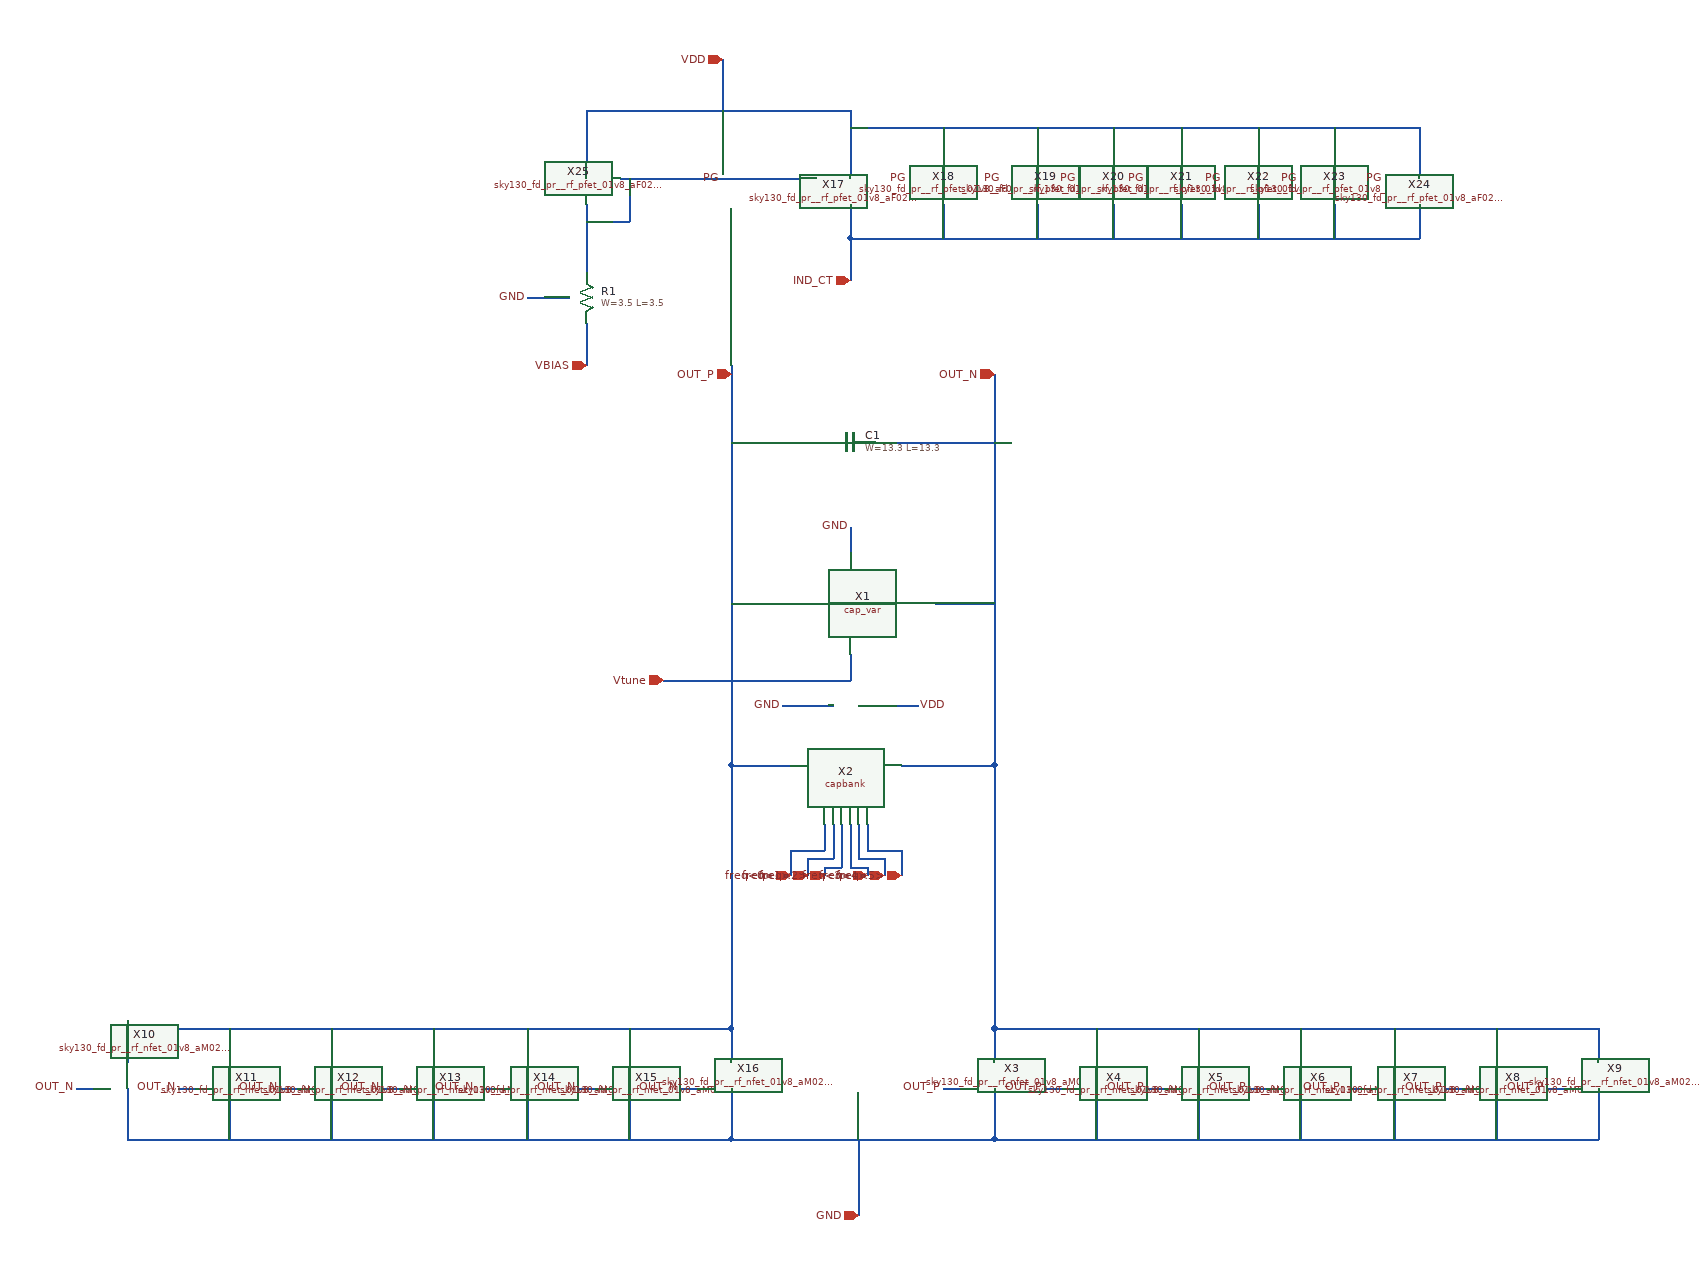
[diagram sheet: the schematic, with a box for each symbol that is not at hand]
v {xschem version=3.0.0 file_version=1.2 }
G {}
K {}
V {}
S {}
E {}
N 290 -420 360 -420 {
lab=OUT_P}
N 290 -820 290 -420 {
lab=OUT_P}
N 290 -800 400 -800 {
lab=OUT_P}
N 290 -610 330 -610 {
lab=OUT_P}
N 490 -420 600 -420 {
lab=OUT_N}
N 600 -820 600 -420 {
lab=OUT_N}
N 460 -800 600 -800 {
lab=OUT_N}
N 530 -610 600 -610 {
lab=OUT_N}
N 290 -890 290 -820 {
lab=OUT_P}
N 600 -880 600 -820 {
lab=OUT_N}
N 430 -550 430 -520 {
lab=Vtune}
N 210 -520 430 -520 {
lab=Vtune}
N 430 -700 430 -670 {
lab=GND}
N 160 -1110 390 -1110 {
lab=PG}
N 430 -1080 430 -1040 {
lab=IND_CT}
N 120 -1190 120 -1140 {
lab=VDD}
N 120 -1190 430 -1190 {
lab=VDD}
N 430 -1190 430 -1140 {
lab=VDD}
N 120 -1140 120 -1110 {
lab=VDD}
N 120 -1080 120 -1000 {
lab=PG}
N 120 -1060 170 -1060 {
lab=PG}
N 170 -1110 170 -1060 {
lab=PG}
N 120 -940 120 -890 {
lab=VBIAS}
N 50 -970 100 -970 {
lab=GND}
N 430 -1140 430 -1110 {
lab=VDD}
N 540 -1080 540 -1040 {
lab=IND_CT}
N 650 -1080 650 -1040 {
lab=IND_CT}
N 740 -1080 740 -1040 {
lab=IND_CT}
N 820 -1080 820 -1040 {
lab=IND_CT}
N 910 -1080 910 -1040 {
lab=IND_CT}
N 1000 -1080 1000 -1040 {
lab=IND_CT}
N 1100 -1080 1100 -1040 {
lab=IND_CT}
N 1100 -1170 1100 -1110 {
lab=VDD}
N 1000 -1170 1000 -1110 {
lab=VDD}
N 910 -1170 910 -1110 {
lab=VDD}
N 820 -1170 820 -1110 {
lab=VDD}
N 740 -1170 740 -1110 {
lab=VDD}
N 650 -1170 650 -1110 {
lab=VDD}
N 540 -1170 540 -1110 {
lab=VDD}
N 430 -1170 1100 -1170 {
lab=VDD}
N 430 -1040 1100 -1040 {
lab=IND_CT}
N 430 -1040 430 -990 {
lab=IND_CT}
N 400 -350 400 -320 {
lab=freq<0>}
N 410 -350 410 -320 {
lab=freq<1>}
N 420 -350 420 -320 {
lab=freq<2>}
N 430 -350 430 -320 {
lab=freq<3>}
N 440 -350 440 -320 {
lab=freq<4>}
N 450 -350 450 -320 {
lab=freq<5>}
N 370 -320 400 -320 {
lab=freq<0>}
N 410 -320 410 -310 {
lab=freq<1>}
N 390 -310 410 -310 {
lab=freq<1>}
N 420 -320 420 -300 {
lab=freq<2>}
N 430 -320 430 -310 {
lab=freq<3>}
N 450 -320 490 -320 {
lab=freq<5>}
N 490 -320 490 -300 {
lab=freq<5>}
N 440 -320 440 -310 {
lab=freq<4>}
N 440 -310 470 -310 {
lab=freq<4>}
N 470 -310 470 -300 {
lab=freq<4>}
N 430 -310 430 -300 {
lab=freq<3>}
N 430 -300 450 -300 {
lab=freq<3>}
N 450 -300 450 -290 {
lab=freq<3>}
N 470 -300 470 -290 {
lab=freq<4>}
N 490 -300 490 -290 {
lab=freq<5>}
N 400 -300 420 -300 {
lab=freq<2>}
N 400 -300 400 -290 {
lab=freq<2>}
N 380 -310 390 -310 {
lab=freq<1>}
N 380 -310 380 -290 {
lab=freq<1>}
N 360 -320 370 -320 {
lab=freq<0>}
N 360 -320 360 -290 {
lab=freq<0>}
N 350 -490 410 -490 {
lab=GND}
N 440 -490 510 -490 {
lab=VDD}
N 280 -1250 280 -1190 {
lab=VDD}
N 600 -40 600 -10 {
lab=GND}
N 600 -10 600 20 {
lab=GND}
N 600 -110 600 -70 {
lab=OUT_N}
N 540 -40 560 -40 {
lab=OUT_P}
N 720 -40 720 -10 {
lab=GND}
N 720 -10 720 20 {
lab=GND}
N 720 -110 720 -70 {
lab=OUT_N}
N 660 -40 680 -40 {
lab=OUT_P}
N 840 -40 840 -10 {
lab=GND}
N 840 -10 840 20 {
lab=GND}
N 840 -110 840 -70 {
lab=OUT_N}
N 780 -40 800 -40 {
lab=OUT_P}
N 960 -40 960 -10 {
lab=GND}
N 960 -10 960 20 {
lab=GND}
N 960 -110 960 -70 {
lab=OUT_N}
N 900 -40 920 -40 {
lab=OUT_P}
N 1070 -40 1070 -10 {
lab=GND}
N 1070 -10 1070 20 {
lab=GND}
N 1070 -110 1070 -70 {
lab=OUT_N}
N 1010 -40 1030 -40 {
lab=OUT_P}
N 1190 -40 1190 -10 {
lab=GND}
N 1190 -10 1190 20 {
lab=GND}
N 1190 -110 1190 -70 {
lab=OUT_N}
N 1130 -40 1150 -40 {
lab=OUT_P}
N 1310 -40 1310 -10 {
lab=GND}
N 1310 -10 1310 20 {
lab=GND}
N 1310 -110 1310 -70 {
lab=OUT_N}
N 1250 -40 1270 -40 {
lab=OUT_P}
N 600 20 1310 20 {
lab=GND}
N 600 -110 1310 -110 {
lab=OUT_N}
N 600 -420 600 -120 {
lab=OUT_N}
N 600 -120 600 -110 {
lab=OUT_N}
N -420 -40 -420 -10 {
lab=GND}
N -420 -10 -420 20 {
lab=GND}
N -420 -110 -420 -70 {
lab=OUT_P}
N -480 -40 -460 -40 {
lab=OUT_N}
N -300 -40 -300 -10 {
lab=GND}
N -300 -10 -300 20 {
lab=GND}
N -300 -110 -300 -70 {
lab=OUT_P}
N -360 -40 -340 -40 {
lab=OUT_N}
N -180 -40 -180 -10 {
lab=GND}
N -180 -10 -180 20 {
lab=GND}
N -180 -110 -180 -70 {
lab=OUT_P}
N -240 -40 -220 -40 {
lab=OUT_N}
N -60 -40 -60 -10 {
lab=GND}
N -60 -10 -60 20 {
lab=GND}
N -60 -110 -60 -70 {
lab=OUT_P}
N -120 -40 -100 -40 {
lab=OUT_N}
N 50 -40 50 -10 {
lab=GND}
N 50 -10 50 20 {
lab=GND}
N 50 -110 50 -70 {
lab=OUT_P}
N -10 -40 10 -40 {
lab=OUT_N}
N 170 -40 170 -10 {
lab=GND}
N 170 -10 170 20 {
lab=GND}
N 170 -110 170 -70 {
lab=OUT_P}
N 110 -40 130 -40 {
lab=OUT_N}
N 290 -40 290 -10 {
lab=GND}
N 290 -10 290 20 {
lab=GND}
N 290 -110 290 -70 {
lab=OUT_P}
N 230 -40 250 -40 {
lab=OUT_N}
N -420 20 290 20 {
lab=GND}
N -420 -110 290 -110 {
lab=OUT_P}
N -420 -120 -420 -110 {
lab=OUT_P}
N 290 -420 290 -110 {
lab=OUT_P}
N 290 20 600 20 {
lab=GND}
N 440 20 440 110 {
lab=GND}
C {cap_var.sym} 330 -550 0 0 {name=X1}
C {capbank.sym} 360 -350 0 0 {name=X2}
C {sky130_fd_pr/cap_mim_m3_1.sym} 430 -800 3 0 {name=C1 model=cap_mim_m3_1 W=13.3 L=13.3 MF=1 spiceprefix=X}
C {devices/iopin.sym} 290 -880 3 0 {name=p1 lab=OUT_P}
C {devices/iopin.sym} 600 -880 3 0 {name=p2 lab=OUT_N}
C {devices/lab_pin.sym} 430 -700 0 0 {name=l1 sig_type=std_logic lab=GND}
C {sky130_fd_pr/res_high_po.sym} 120 -970 0 0 {name=R1
W=3.5
L=3.5
model=res_high_po
spiceprefix=X
mult=1}
C {devices/lab_pin.sym} 50 -970 0 0 {name=l2 sig_type=std_logic lab=GND}
C {sky130_fd_pr__rf_pfet_01v8_aF02W3p00L0p15.sym} 390 -1080 0 0 {name=X17
model=rf_pfet_01v8_aF02W3p00L0p15pfet_01v8
spiceprefix=X
}
C {sky130_fd_pr__rf_pfet_01v8_aF02W3p00L0p15.sym} 160 -1080 0 1 {name=X25
model=rf_pfet_01v8_aF02W3p00L0p15pfet_01v8
spiceprefix=X
}
C {sky130_fd_pr__rf_pfet_01v8_aF02W3p00L0p15.sym} 500 -1080 0 0 {name=X18
model=rf_pfet_01v8_aF02W3p00L0p15pfet_01v8
spiceprefix=X
}
C {sky130_fd_pr__rf_pfet_01v8_aF02W3p00L0p15.sym} 610 -1080 0 0 {name=X19
model=rf_pfet_01v8_aF02W3p00L0p15pfet_01v8
spiceprefix=X
}
C {sky130_fd_pr__rf_pfet_01v8_aF02W3p00L0p15.sym} 700 -1080 0 0 {name=X20
model=rf_pfet_01v8_aF02W3p00L0p15pfet_01v8
spiceprefix=X
}
C {sky130_fd_pr__rf_pfet_01v8_aF02W3p00L0p15.sym} 780 -1080 0 0 {name=X21
model=rf_pfet_01v8_aF02W3p00L0p15pfet_01v8
spiceprefix=X
}
C {sky130_fd_pr__rf_pfet_01v8_aF02W3p00L0p15.sym} 870 -1080 0 0 {name=X22
model=rf_pfet_01v8_aF02W3p00L0p15pfet_01v8
spiceprefix=X
}
C {sky130_fd_pr__rf_pfet_01v8_aF02W3p00L0p15.sym} 960 -1080 0 0 {name=X23
model=rf_pfet_01v8_aF02W3p00L0p15pfet_01v8
spiceprefix=X
}
C {sky130_fd_pr__rf_pfet_01v8_aF02W3p00L0p15.sym} 1060 -1080 0 0 {name=X24
model=rf_pfet_01v8_aF02W3p00L0p15pfet_01v8
spiceprefix=X
}
C {devices/lab_pin.sym} 280 -1110 3 0 {name=l3 sig_type=std_logic lab=PG}
C {devices/lab_pin.sym} 500 -1110 3 0 {name=l4 sig_type=std_logic lab=PG}
C {devices/lab_pin.sym} 610 -1110 3 0 {name=l5 sig_type=std_logic lab=PG}
C {devices/lab_pin.sym} 700 -1110 3 0 {name=l6 sig_type=std_logic lab=PG}
C {devices/lab_pin.sym} 780 -1110 3 0 {name=l7 sig_type=std_logic lab=PG}
C {devices/lab_pin.sym} 870 -1110 3 0 {name=l8 sig_type=std_logic lab=PG}
C {devices/lab_pin.sym} 960 -1110 3 0 {name=l9 sig_type=std_logic lab=PG}
C {devices/lab_pin.sym} 1060 -1110 3 0 {name=l10 sig_type=std_logic lab=PG}
C {devices/iopin.sym} 430 -990 1 0 {name=p3 lab=IND_CT}
C {devices/iopin.sym} 120 -890 1 0 {name=p4 lab=VBIAS}
C {devices/iopin.sym} 210 -520 2 0 {name=p5 lab=Vtune}
C {devices/ipin.sym} 360 -290 3 0 {name=p7 lab=freq\\<0\\>}
C {devices/ipin.sym} 380 -290 3 0 {name=p6 lab=freq\\<1\\>}
C {devices/ipin.sym} 400 -290 3 0 {name=p8 lab=freq\\<2\\>}
C {devices/ipin.sym} 450 -290 3 0 {name=p9 lab=freq\\<3\\>}
C {devices/ipin.sym} 470 -290 3 0 {name=p10 lab=freq\\<4\\>}
C {devices/ipin.sym} 490 -290 3 0 {name=p11 lab=freq\\<5\\>}
C {devices/lab_pin.sym} 350 -490 0 0 {name=l11 sig_type=std_logic lab=GND}
C {devices/lab_pin.sym} 510 -490 2 0 {name=l12 sig_type=std_logic lab=VDD}
C {devices/iopin.sym} 280 -1250 3 0 {name=p12 lab=VDD}
C {sky130_fd_pr__rf_nfet_01v8_aM02W5p00L0p15.sym} 560 -10 0 0 {name=X3}
C {devices/lab_pin.sym} 540 -40 0 0 {name=l13 sig_type=std_logic lab=OUT_P}
C {sky130_fd_pr__rf_nfet_01v8_aM02W5p00L0p15.sym} 680 -10 0 0 {name=X4}
C {devices/lab_pin.sym} 660 -40 0 0 {name=l14 sig_type=std_logic lab=OUT_P}
C {sky130_fd_pr__rf_nfet_01v8_aM02W5p00L0p15.sym} 800 -10 0 0 {name=X5}
C {devices/lab_pin.sym} 780 -40 0 0 {name=l15 sig_type=std_logic lab=OUT_P}
C {sky130_fd_pr__rf_nfet_01v8_aM02W5p00L0p15.sym} 920 -10 0 0 {name=X6}
C {devices/lab_pin.sym} 900 -40 0 0 {name=l16 sig_type=std_logic lab=OUT_P}
C {sky130_fd_pr__rf_nfet_01v8_aM02W5p00L0p15.sym} 1030 -10 0 0 {name=X7}
C {devices/lab_pin.sym} 1010 -40 0 0 {name=l17 sig_type=std_logic lab=OUT_P}
C {sky130_fd_pr__rf_nfet_01v8_aM02W5p00L0p15.sym} 1150 -10 0 0 {name=X8}
C {devices/lab_pin.sym} 1130 -40 0 0 {name=l18 sig_type=std_logic lab=OUT_P}
C {sky130_fd_pr__rf_nfet_01v8_aM02W5p00L0p15.sym} 1270 -10 0 0 {name=X9}
C {devices/lab_pin.sym} 1250 -40 0 0 {name=l19 sig_type=std_logic lab=OUT_P}
C {sky130_fd_pr__rf_nfet_01v8_aM02W5p00L0p15.sym} -460 -10 0 0 {name=X10}
C {devices/lab_pin.sym} -480 -40 0 0 {name=l20 sig_type=std_logic lab=OUT_N}
C {sky130_fd_pr__rf_nfet_01v8_aM02W5p00L0p15.sym} -340 -10 0 0 {name=X11}
C {devices/lab_pin.sym} -360 -40 0 0 {name=l21 sig_type=std_logic lab=OUT_N}
C {sky130_fd_pr__rf_nfet_01v8_aM02W5p00L0p15.sym} -220 -10 0 0 {name=X12}
C {devices/lab_pin.sym} -240 -40 0 0 {name=l22 sig_type=std_logic lab=OUT_N}
C {sky130_fd_pr__rf_nfet_01v8_aM02W5p00L0p15.sym} -100 -10 0 0 {name=X13}
C {devices/lab_pin.sym} -120 -40 0 0 {name=l23 sig_type=std_logic lab=OUT_N}
C {sky130_fd_pr__rf_nfet_01v8_aM02W5p00L0p15.sym} 10 -10 0 0 {name=X14}
C {devices/lab_pin.sym} -10 -40 0 0 {name=l24 sig_type=std_logic lab=OUT_N}
C {sky130_fd_pr__rf_nfet_01v8_aM02W5p00L0p15.sym} 130 -10 0 0 {name=X15}
C {devices/lab_pin.sym} 110 -40 0 0 {name=l25 sig_type=std_logic lab=OUT_N}
C {sky130_fd_pr__rf_nfet_01v8_aM02W5p00L0p15.sym} 250 -10 0 0 {name=X16}
C {devices/lab_pin.sym} 230 -40 0 0 {name=l26 sig_type=std_logic lab=OUT_N}
C {devices/iopin.sym} 440 110 1 0 {name=p13 lab=GND}
